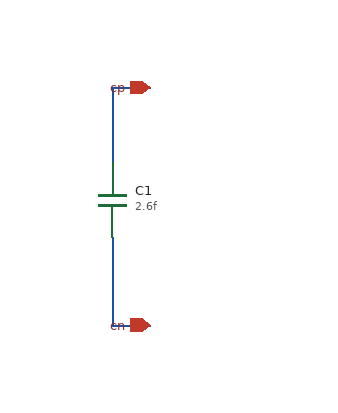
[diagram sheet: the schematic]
v {xschem version=3.0.0 file_version=1.2 }
G {}
K {}
V {}
S {}
E {}
N 390 -520 420 -520 {
lab=xxx}
N 390 -520 390 -460 {
lab=xxx}
N 390 -400 390 -330 {
lab=cn}
N 390 -330 420 -330 {
lab=cn}
C {capa.sym} 390 -430 0 0 {name=C1
m=1
value=2.6f
ic=0}
C {iopin.sym} 420 -520 0 0 {name=p1 lab=cp}
C {iopin.sym} 420 -330 0 0 {name=p2 lab=cn}
